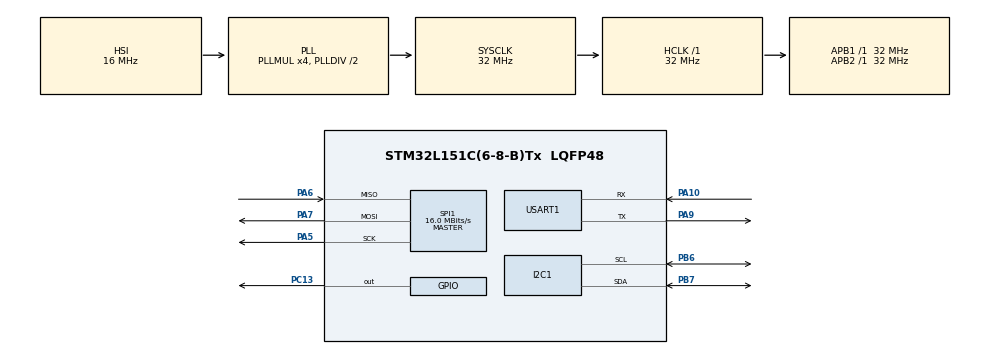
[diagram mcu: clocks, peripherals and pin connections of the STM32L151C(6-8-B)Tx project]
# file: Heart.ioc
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FREERTOS.Tasks01=defaultTask,24,128,StartDefaultTask,Default,NULL,Dynamic,NULL,NULL;myTask02,8,128,StartTask02,Default,NULL,Dynamic,NULL,NULL;myTask03,8,128,StartTask03,Default,NULL,Dynamic,NULL,NULL;myTask04,8,128,StartTask04,Default,NULL,Dynamic,NULL,NULL
Mcu.Family=STM32L1
Mcu.Name=STM32L151C(6-8-B)Tx
Mcu.Package=LQFP48
NVIC.PriorityGroup=NVIC_PRIORITYGROUP_4
NVIC.USART1_IRQn=true\:0\:0\:false\:false\:true\:true\:true\:true
PA10.Mode=Asynchronous
PA10.Signal=USART1_RX
PA5.Mode=Full_Duplex_Master
PA5.Signal=SPI1_SCK
PA6.Mode=Full_Duplex_Master
PA6.Signal=SPI1_MISO
PA7.Mode=Full_Duplex_Master
PA7.Signal=SPI1_MOSI
PA9.Mode=Asynchronous
PA9.Signal=USART1_TX
PB6.Mode=I2C
PB6.Signal=I2C1_SCL
PB7.Mode=I2C
PB7.Signal=I2C1_SDA
PC13-WKUP2.Signal=GPIO_Output
ProjectManager.HeapSize=0x200
ProjectManager.StackSize=0x400
ProjectManager.TargetToolchain=MDK-ARM V5.27
RCC.48MHZClocksFreq_Value=32000000
RCC.AHBFreq_Value=32000000
RCC.APB1Freq_Value=32000000
RCC.APB1TimFreq_Value=32000000
RCC.APB2Freq_Value=32000000
RCC.APB2TimFreq_Value=32000000
RCC.HCLKFreq_Value=32000000
RCC.HSE_VALUE=24000000
RCC.HSI_VALUE=16000000
RCC.LSE_VALUE=32768
RCC.MSI_VALUE=2097000
RCC.PLLMUL=RCC_PLL_MUL4
RCC.SYSCLKFreq_VALUE=32000000
RCC.SYSCLKSource=RCC_SYSCLKSOURCE_PLLCLK
RCC.VCOOutputFreq_Value=64000000
SPI1.BaudRatePrescaler=SPI_BAUDRATEPRESCALER_2
SPI1.CLKPolarity=SPI_POLARITY_LOW
SPI1.CalculateBaudRate=16.0 MBits/s
SPI1.Direction=SPI_DIRECTION_2LINES
SPI1.Mode=SPI_MODE_MASTER
SPI1.VirtualType=VM_MASTER
USART1.VirtualMode=VM_ASYNC
VP_FREERTOS_VS_CMSIS_V2.Mode=CMSIS_V2
board=custom

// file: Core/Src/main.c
/* USER CODE BEGIN Header */
/**
  ******************************************************************************
  * @file           : main.c
  * @brief          : Main program body
  ******************************************************************************
  * @attention
  *
  * <h2><center>&copy; Copyright (c) 2021 STMicroelectronics.
  * All rights reserved.</center></h2>
  *
  * This software component is licensed by ST under Ultimate Liberty license
  * SLA0044, the "License"; You may not use this file except in compliance with
  * the License. You may obtain a copy of the License at:
  *                             www.st.com/SLA0044
  *
  ******************************************************************************
  */
/* USER CODE END Header */
#include "main.h"
#include "cmsis_os.h"
#include "MAX30102.h"
#include "stdio.h"
#include "oled.h"
char data_save;
int heart;
int red_reg[200];
int led_reg[200];
int heart_reg;
char online=1;
int reg_num=0;
int reg_heart=1;
unsigned char pData[8];
float spo2;
int flag=3;
unsigned char char_show=0;
I2C_HandleTypeDef hi2c1;

SPI_HandleTypeDef hspi1;

UART_HandleTypeDef huart1;

osThreadId_t defaultTaskHandle;
#ifdef __GNUC__
  /* With GCC/RAISONANCE, small printf (option LD Linker->Libraries->Small printf
     set to 'Yes') calls __io_putchar() */
  #define PUTCHAR_PROTOTYPE int __io_putchar(int ch)
#else
  #define PUTCHAR_PROTOTYPE int fputc(int ch, FILE *f)
#endif /* __GNUC__ */
PUTCHAR_PROTOTYPE
{
  /* Place your implementation of fputc here */
  /* e.g. write a character to the USART */
	huart1.Instance->DR = (uint8_t) ch;

  /* Loop until the end of transmission */
	while(__HAL_UART_GET_FLAG(&huart1, UART_FLAG_TC) == RESET){}

  return ch;
}
const osThreadAttr_t defaultTask_attributes = {
  .name = "defaultTask",
  .priority = (osPriority_t) osPriorityNormal,
  .stack_size = 128 * 4
};
osThreadId_t myTask02Handle;
const osThreadAttr_t myTask02_attributes = {
  .name = "myTask02",
  .priority = (osPriority_t) osPriorityLow,
  .stack_size = 128 * 6
};
osThreadId_t myTask03Handle;
const osThreadAttr_t myTask03_attributes = {
  .name = "myTask03",
  .priority = (osPriority_t) osPriorityLow,
  .stack_size = 128 * 4
};
osThreadId_t myTask04Handle;
const osThreadAttr_t myTask04_attributes = {
  .name = "myTask04",
  .priority = (osPriority_t) osPriorityLow,
  .stack_size = 128 * 4
};
void SystemClock_Config(void);
static void MX_GPIO_Init(void);
static void MX_I2C1_Init(void);
static void MX_SPI1_Init(void);
static void MX_USART1_UART_Init(void);
void StartDefaultTask(void *argument);
void StartTask02(void *argument);
void StartTask03(void *argument);
void StartTask04(void *argument);

int main(void)
{

  /* MCU Configuration--------------------------------------------------------*/

  /* Reset of all peripherals, Initializes the Flash interface and the Systick. */
  HAL_Init();

  /* Configure the system clock */
  SystemClock_Config();

  /* Initialize all configured peripherals */
  MX_GPIO_Init();
  MX_I2C1_Init();
  MX_SPI1_Init();
  MX_USART1_UART_Init();
	OLED_Init();

  osKernelInitialize();

  defaultTaskHandle = osThreadNew(StartDefaultTask, NULL, &defaultTask_attributes);

  myTask02Handle = osThreadNew(StartTask02, NULL, &myTask02_attributes);

  myTask03Handle = osThreadNew(StartTask03, NULL, &myTask03_attributes);

  myTask04Handle = osThreadNew(StartTask04, NULL, &myTask04_attributes);

  /* Start scheduler */
	maxim_max30102_reset();
  osKernelStart();

  /* We should never get here as control is now taken by the scheduler */
  /* Infinite loop */
  while (1)
  {

  }
}

void SystemClock_Config(void)
{
  RCC_OscInitTypeDef RCC_OscInitStruct = {0};
  RCC_ClkInitTypeDef RCC_ClkInitStruct = {0};

  /** Configure the main internal regulator output voltage
  */
  __HAL_PWR_VOLTAGESCALING_CONFIG(PWR_REGULATOR_VOLTAGE_SCALE1);
  /** Initializes the RCC Oscillators according to the specified parameters
  * in the RCC_OscInitTypeDef structure.
  */
  RCC_OscInitStruct.OscillatorType = RCC_OSCILLATORTYPE_HSI;
  RCC_OscInitStruct.HSIState = RCC_HSI_ON;
  RCC_OscInitStruct.HSICalibrationValue = RCC_HSICALIBRATION_DEFAULT;
  RCC_OscInitStruct.PLL.PLLState = RCC_PLL_ON;
  RCC_OscInitStruct.PLL.PLLSource = RCC_PLLSOURCE_HSI;
  RCC_OscInitStruct.PLL.PLLMUL = RCC_PLL_MUL4;
  RCC_OscInitStruct.PLL.PLLDIV = RCC_PLL_DIV2;
  if (HAL_RCC_OscConfig(&RCC_OscInitStruct) != HAL_OK)
  {
    Error_Handler();
  }
  /** Initializes the CPU, AHB and APB buses clocks
  */
  RCC_ClkInitStruct.ClockType = RCC_CLOCKTYPE_HCLK|RCC_CLOCKTYPE_SYSCLK
                              |RCC_CLOCKTYPE_PCLK1|RCC_CLOCKTYPE_PCLK2;
  RCC_ClkInitStruct.SYSCLKSource = RCC_SYSCLKSOURCE_PLLCLK;
  RCC_ClkInitStruct.AHBCLKDivider = RCC_SYSCLK_DIV1;
  RCC_ClkInitStruct.APB1CLKDivider = RCC_HCLK_DIV1;
  RCC_ClkInitStruct.APB2CLKDivider = RCC_HCLK_DIV1;

  if (HAL_RCC_ClockConfig(&RCC_ClkInitStruct, FLASH_LATENCY_1) != HAL_OK)
  {
    Error_Handler();
  }
}

static void MX_I2C1_Init(void)
{

  hi2c1.Instance = I2C1;
  hi2c1.Init.ClockSpeed = 100000;
  hi2c1.Init.DutyCycle = I2C_DUTYCYCLE_2;
  hi2c1.Init.OwnAddress1 = 0;
  hi2c1.Init.AddressingMode = I2C_ADDRESSINGMODE_7BIT;
  hi2c1.Init.DualAddressMode = I2C_DUALADDRESS_DISABLE;
  hi2c1.Init.OwnAddress2 = 0;
  hi2c1.Init.GeneralCallMode = I2C_GENERALCALL_DISABLE;
  hi2c1.Init.NoStretchMode = I2C_NOSTRETCH_DISABLE;
  if (HAL_I2C_Init(&hi2c1) != HAL_OK)
  {
    Error_Handler();
  }

}

static void MX_SPI1_Init(void)
{

  /* SPI1 parameter configuration*/
  hspi1.Instance = SPI1;
  hspi1.Init.Mode = SPI_MODE_MASTER;
  hspi1.Init.Direction = SPI_DIRECTION_2LINES;
  hspi1.Init.DataSize = SPI_DATASIZE_8BIT;
  hspi1.Init.CLKPolarity = SPI_POLARITY_LOW;
  hspi1.Init.CLKPhase = SPI_PHASE_1EDGE;
  hspi1.Init.NSS = SPI_NSS_SOFT;
  hspi1.Init.BaudRatePrescaler = SPI_BAUDRATEPRESCALER_2;
  hspi1.Init.FirstBit = SPI_FIRSTBIT_MSB;
  hspi1.Init.TIMode = SPI_TIMODE_DISABLE;
  hspi1.Init.CRCCalculation = SPI_CRCCALCULATION_DISABLE;
  hspi1.Init.CRCPolynomial = 10;
  if (HAL_SPI_Init(&hspi1) != HAL_OK)
  {
    Error_Handler();
  }

}

static void MX_USART1_UART_Init(void)
{

  huart1.Instance = USART1;
  huart1.Init.BaudRate = 115200;
  huart1.Init.WordLength = UART_WORDLENGTH_8B;
  huart1.Init.StopBits = UART_STOPBITS_1;
  huart1.Init.Parity = UART_PARITY_NONE;
  huart1.Init.Mode = UART_MODE_TX_RX;
  huart1.Init.HwFlowCtl = UART_HWCONTROL_NONE;
  huart1.Init.OverSampling = UART_OVERSAMPLING_16;
  if (HAL_UART_Init(&huart1) != HAL_OK)
  {
    Error_Handler();
  }

}

static void MX_GPIO_Init(void)
{
  GPIO_InitTypeDef GPIO_InitStruct = {0};

  /* GPIO Ports Clock Enable */
  __HAL_RCC_GPIOC_CLK_ENABLE();
  __HAL_RCC_GPIOA_CLK_ENABLE();
  __HAL_RCC_GPIOB_CLK_ENABLE();

  /*Configure GPIO pin Output Level */
  HAL_GPIO_WritePin(GPIOC, GPIO_PIN_13, GPIO_PIN_SET);

  /*Configure GPIO pin : PC13 */
  GPIO_InitStruct.Pin = GPIO_PIN_13;
  GPIO_InitStruct.Mode = GPIO_MODE_OUTPUT_PP;
  GPIO_InitStruct.Pull = GPIO_NOPULL;
  GPIO_InitStruct.Speed = GPIO_SPEED_FREQ_HIGH;
  HAL_GPIO_Init(GPIOC, &GPIO_InitStruct);

	HAL_GPIO_WritePin(GPIOA, GPIO_PIN_0, GPIO_PIN_SET);

  /*Configure GPIO pin : PC13 */
  GPIO_InitStruct.Pin = GPIO_PIN_0;
  GPIO_InitStruct.Mode = GPIO_MODE_OUTPUT_PP;
  GPIO_InitStruct.Pull = GPIO_NOPULL;
  GPIO_InitStruct.Speed = GPIO_SPEED_FREQ_HIGH;
  HAL_GPIO_Init(GPIOA, &GPIO_InitStruct);

  HAL_GPIO_WritePin(GPIOA, GPIO_PIN_1, GPIO_PIN_SET);

  /*Configure GPIO pin : PC13 */
  GPIO_InitStruct.Pin = GPIO_PIN_1;
  GPIO_InitStruct.Mode = GPIO_MODE_OUTPUT_PP;
  GPIO_InitStruct.Pull = GPIO_NOPULL;
  GPIO_InitStruct.Speed = GPIO_SPEED_FREQ_HIGH;
  HAL_GPIO_Init(GPIOA, &GPIO_InitStruct);
}

void StartDefaultTask(void *argument)
{
	float r;
	float red;
	float led;
	int red_last=0;
	int led_last=0;
	int cha=0;
	int reg_num1=0;
	int reg_num2=0;
	int pot_i=0;
  while (1)
  {
		HAL_I2C_Mem_Read(&hi2c1,I2C_READ_ADDR,REG_FIFO_DATA,I2C_MEMADD_SIZE_8BIT,(unsigned char *)pData,8,1000);
		red=(red+(((pData[3]&0x03)<<16)|(pData[4]<<8)|(pData[5])))/2;
		led=(led+(((pData[0]&0x03)<<16)|(pData[1]<<8)|(pData[2])))/2;
		if(red>5000){		//判断采集状态
			if(flag!=1) {OLED_Clear();flag=1;}
			online=1;
		  cha=(cha+red-red_last)/2;  //求导
		  if(cha<-10){data_save=data_save<<1|0;}
		  else data_save=data_save<<1|1;
		  r=red/led;
		  spo2=-45.060*r*r+30.354*r + 94.845;
			if(pot_i<128){ 														//波形图显示
			OLED_DrawPoint(++pot_i,25-cha/6);}      //波形显示过大可把12调大，波形过小可调小12
			else {
			OLED_Clear();
			pot_i=0;
			}
		}
		else
		{
			if(flag!=0) {
				OLED_Clear();
				flag=0;
				OLED_Clear();
				pot_i=0;
				data_save=0xff;
				heart=0;
				online=0;
				reg_heart=0;
				reg_num=0;
				spo2=0;
			}
			OLED_ShowChar(1,2,"No FINGER!");
		}
    printf("a:%d,%d,%f,%f\n",cha,heart,red,spo2);
		red_last=red;
		maxim_max30102_write_reg(0x21,0x01);
		vTaskDelay(10);
  }
}
void StartTask02(void *argument)
{
  while(1)
	{
		if(char_show==0){
		OLED_ShowChar(3,0,"H:");
		OLED_ShowNums(3,2,heart,3);
		OLED_ShowChar(3,6,"Spo2:");
		OLED_ShowNums(3,11,spo2,3);
		vTaskDelay(10);
		}
	}
}
void StartTask03(void *argument)
{
	int last;
	int now;
	int c;
	int num=1;

  while(1){
		if((data_save&0xf0)==0x00)
		{
		now=HAL_GetTick();
		if(now<last){c=(0xffffffff-last+now);}
		else c=(now-last);
		if(c>=300)
		{
			heart=60000/c;
			last=now;
			reg_heart=(reg_heart*reg_num+heart)/(reg_num+1);
			if(reg_num==30){
				heart_reg=reg_heart;
				reg_num=0;
				reg_heart=0;
			}
			else
				reg_num++;
		}
		}
	}
}
void StartTask04(void *argument)
{

  for(;;)
  {
    osDelay(1);
  }

}
void Error_Handler(void)
{
}

/************************ (C) COPYRIGHT STMicroelectronics *****END OF FILE****/
